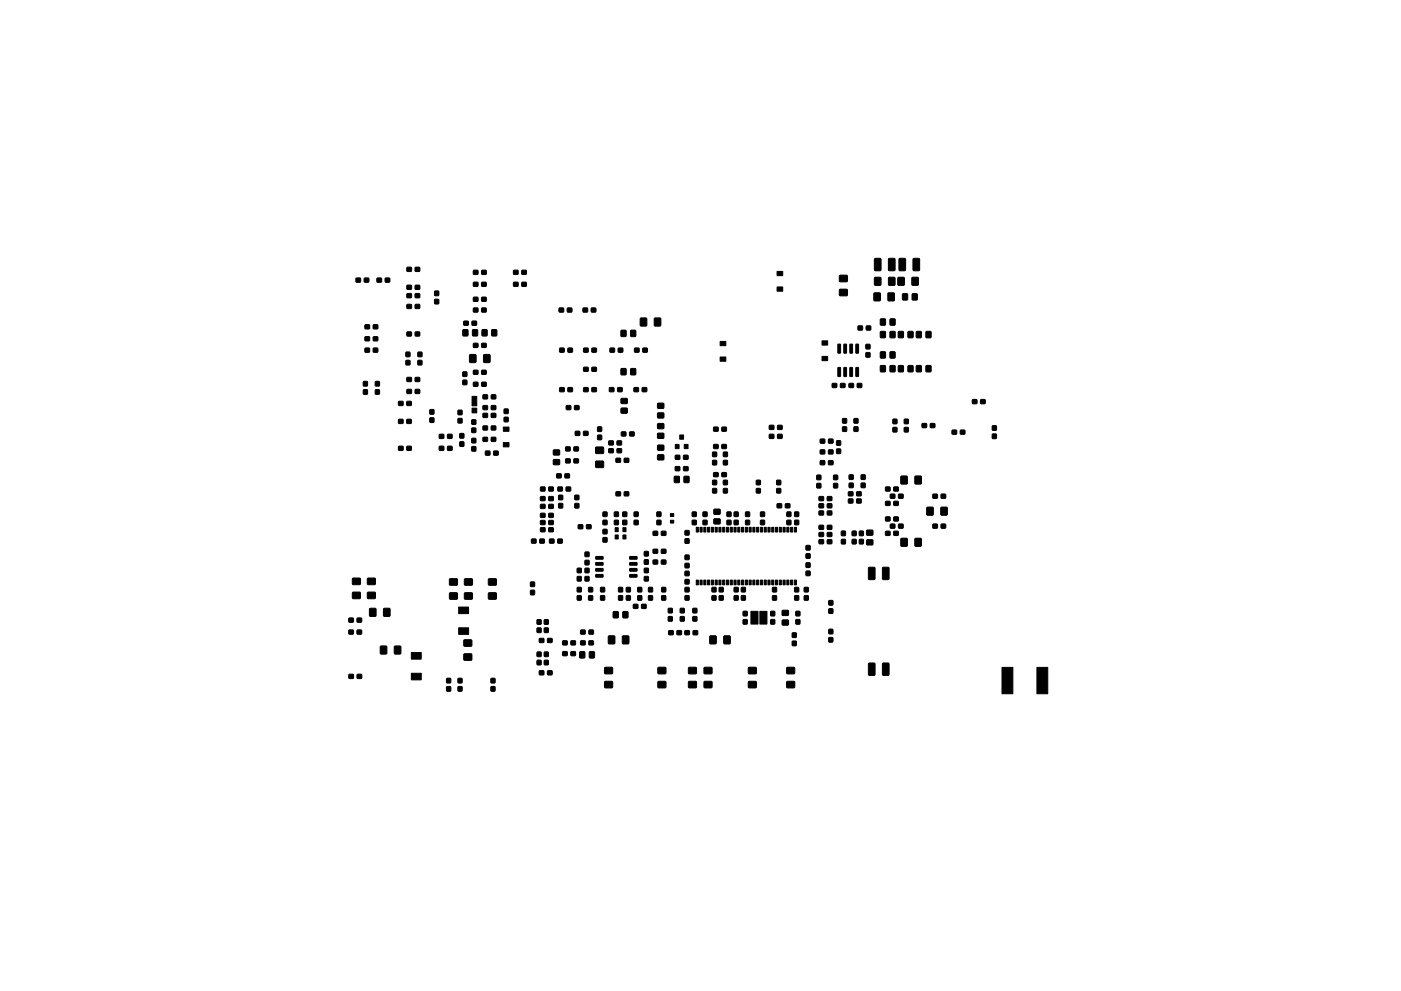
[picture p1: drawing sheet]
<svg xmlns="http://www.w3.org/2000/svg" width="297mm" height="210mm" viewBox="0 0 297 210" stroke-linecap="round" stroke-linejoin="round" font-family="sans-serif">
<g fill="#000" stroke="#000" stroke-width=".21">
<path d="M75.5 59h.9v.8l-.9 .1zM77.3 59h.8l.1 .8-.9 .1zM79.9 59h.9l.1 .8-.9 .1zM81.7 59h.9v.8l-.9 .1zM86.3 56.7h.9v.8l-.9 .1zM88 56.7h.9l.1 .8-.9 .1zM100.4 59.9h.9v.8h-.9zM100.4 57.4h.9v.8h-.9zM102.1 59.9h.9l.1 .8h-.9zM102.1 57.4h.9l.1 .8h-.9zM108.9 59.9h.9v.8h-.9zM108.9 57.4h.9v.8h-.9z"/>
<path d="M110.7 59.9h.8l.1 .8h-.9zM110.7 57.4h.8l.1 .8h-.9zM164.8 57.6h1.2v.9h-1.2zM178 58.4h1.6v1.3h-1.6zM185.5 58.9h1.2v1.6h-1.3zM185.5 54.9l1.1-.1 .2 .2v2.2l-.2 .2-1 .1-.2-.2zM188.4 58.9h1.3v1.6h-1.3zM188.4 54.9l1.2-.1 .2 .2v2.2l-.2 .2-1 .1-.2-.2zM190.4 58.9h1.3v1.6h-1.3zM190.7 54.9l1.1-.1 .2 .2v2.2l-.1 .2-1.1 .1-.2-.2zM193.4 58.9h1.3l-.1 1.6h-1.2zM193.6 54.9l1.2-.1 .2 .2v2.2l-.2 .2-1 .1-.2-.2z"/>
<path d="M77.4 68.9h.9v.8l-.9 .1zM77.4 71.5h.9v.8h-.9zM77.4 73.9h.9v.8h-.9zM79.2 68.9h.9v.8l-.9 .1zM79.2 71.5h.9v.8h-.9zM79.2 73.9h.9v.8h-.9zM86.1 76.5h.8v.9h-.8zM86.1 74.7l.8 .1v.9l-.8-.1zM86.3 60.5h.9v.8l-.9 .1zM86.3 70.5l.9-.1v.8l-.9 .1zM86.3 62.3h.9v.8l-.9 .1zM86.3 64.6h.9v.8h-.9z"/>
<path d="M88 60.5h.9l.1 .8-.9 .1zM88 70.5l.9-.1 .1 .8-.9 .1zM88 62.3h.9l.1 .8-.9 .1zM88 64.6h.9l.1 .8h-.9zM88.6 76.5h.8v.9h-.8zM88.6 74.7l.8 .1v.9l-.8-.1zM92.2 63.5l.8 .1v.9l-.8-.1zM92.2 61.8h.8v.9h-.8zM98.1 78.9h.9l-.1 1-.8-.1zM98.2 70h1v1.2h-1zM98.4 68.2h.8l.1 .8h-.9zM99.6 75.3h1.3v1.6h-1.3z"/>
<path d="M100.1 68.2h.9v.8h-.9zM100.2 70h1v1.2h-1zM100.4 65.4h.9v.8h-.9zM100.4 63.1h.9v.8h-.9zM100.4 72.9h.9v.8h-.9zM100.4 78.6h.9v.8h-.9zM102.1 65.4h.9l.1 .8h-.9zM102.1 63.1h.9l.1 .8h-.9zM102.1 72.9h.9l.1 .8h-.9zM102.1 78.6h.9l.1 .8h-.9zM102.2 70h1.1l-.1 1.2h-1zM102.6 75.3h1.3l-.1 1.6h-1.2z"/>
<path d="M104.3 70h1v1.2h-1zM118.6 65.4h.9v.8h-.9zM118.7 73.9h.9v.8h-.9zM120.3 65.4h.9v.8h-.9zM120.4 73.9h.9l.1 .8h-.9zM123.6 65.4h.9l.1 .8h-.9zM123.8 77.9h.9v.8l-.9 .1zM123.8 73.9h.9v.8h-.9zM125.4 65.4h.9v.8h-.9zM125.5 77.9h.9v.8l-.9 .1zM125.5 73.9h.9v.8h-.9zM129.4 73.9h.8l.1 .8h-.9z"/>
<path d="M131.1 73.9h.9v.8h-.9zM131.7 70.1h1v1.3l-1-.1zM131.7 78.2l1 .1v1.2h-1zM133.7 70.1h1.1l-.1 1.3-1-.1zM133.7 78.2l1.1 .1-.1 1.2h-1zM134.6 73.9h.9v.8h-.9zM135.8 67.5h1.3v1.6h-1.3zM136.3 73.9h.9v.8h-.9zM138.8 67.5h1.3l-.1 1.6h-1.2zM152.7 72.4h1.2v.9h-1.2zM152.7 75.7h1.2v.9h-1.2zM164.8 60.9h1.2v.9h-1.2z"/>
<path d="M174.3 72.3h1.2v.9h-1.2zM174.3 75.6h1.2v.9h-1.2zM177.7 78l.5 .1v1.7l-.1 .1-.5-.1zM177.7 73l.5 .1v1.7l-.1 .1-.5-.1zM178.9 78l.6 .1v1.7l-.1 .1-.5-.1zM178.9 73l.6 .1v1.7l-.1 .1-.5-.1zM178 61.4h1.6v1.3h-1.6zM180.2 78l.6 .1v1.7l-.2 .1-.4-.1zM180.2 73l.6 .1v1.7l-.2 .1-.4-.1zM181.5 78l.5 .1v1.7l-.1 .1-.5-.1zM181.5 73l.5 .1v1.7l-.1 .1-.5-.1zM181.9 69.2h.9l.1 .8h-1z"/>
<path d="M183.6 74.8l.8 .1v.9l-.8-.1zM183.6 73.1h.8v.9h-.8zM183.7 69.2h.9v.8h-.9zM185.3 62.2h1.3v1.6h-1.3zM186.7 77.6h1v1.3l-1-.1zM186.7 67.7h1v1.3l-1-.1zM186.7 74.7h1v1.2h-1zM186.7 70.4h1v1.2h-1zM188.3 62.2h1.3v1.6h-1.3zM188.7 77.6h1.1l-.1 1.3-1-.1zM188.7 67.7h1.1l-.1 1.3-1-.1zM188.7 74.7h1.1l-.1 1.2h-1z"/>
<path d="M188.7 70.4h1.1l-.1 1.2h-1zM190.5 70.4h1v1.2h-1zM190.5 77.6h1v1.3l-1-.1zM191.4 62.4h1v1.2h-1zM192.5 70.4h1.1l-.1 1.2h-1zM192.5 77.6h1.1l-.1 1.3-1-.1zM193.4 62.4h1.1l-.1 1.2h-1zM194.3 70.4h1v1.2h-1zM194.3 77.6h1v1.3l-1-.1zM196.4 70.4h1l-.1 1.2h-1zM196.4 77.6h1l-.1 1.3-1-.1zM77.1 82.7h.8v.9h-.9z"/>
<path d="M77.1 81h.8v.9h-.9zM79.6 82.7h.8v.9h-.8zM79.6 81h.8v.9h-.8zM84.5 89h.9v.8h-.9zM84.5 94.7h.9v.8h-.9zM84.5 85.2h.9v.8h-.9zM86.3 89h.9v.8h-.9zM86.3 94.7h.9v.8h-.9zM86.3 85.2h.9v.8h-.9zM86.3 80.1h.9v.8h-.9zM86.3 82.6h.9v.8l-.9 .1zM88 80.1h.9l.1 .8h-.9z"/>
<path d="M88 82.6h.9l.1 .8-.9 .1zM91.2 88.7h.8v.9h-.9zM91.2 86.9h.8v1l-.9-.1zM93.2 92.2h.9v.8h-.9zM93.2 94.7h.9v.8h-.9zM94.9 92.2h.9v.8h-.9zM94.9 94.7h.9v.8h-.9zM97.1 88.8h.9l-.1 .9h-.8zM97.1 87.1h.9l-.1 .9-.8-.1zM97.5 92h.8v.9h-.8zM97.5 93.8h.8v.9h-.8zM98.1 80.7h.9l-.1 .9h-.8z"/>
<path d="M100.1 84.1h1v2h-1zM100.1 86.6h1v1h-1zM100.1 90.8l.8 .1-.1 .9-.8-.1zM100.1 89.1h.8l-.1 .9h-.8zM100.1 94.8h.8l-.1 .9h-.8zM100.1 93h.8l-.1 1-.8-.1zM100.4 81.1h.9v.8h-.9zM102.1 81.1h.9l.1 .8h-.9zM102.4 86.1h.9l.1 .8h-1zM102.4 92.8h.9l.1 .8h-1zM102.4 87.7h.9l.1 .8-1 .1zM102.4 90.4h.9l.1 .8h-1z"/>
<path d="M102.4 83.8h.9l.1 .8h-1zM102.9 95.7h.9l.1 .8-.9 .1zM104.2 86.1h.9v.8h-.9zM104.2 92.8h.9v.8h-.9zM104.2 87.7h.9v.8l-.9 .1zM104.2 90.4h.9v.8h-.9zM104.2 83.8h.9v.8h-.9zM104.7 95.7h.9v.8l-.9 .1zM106.9 86.8h.8v.9h-.8zM106.9 88.6h.8v.9l-.8-.1zM106.7 90.6h1.2v.9h-1.2zM106.7 93.9h1.2v.9h-1.2z"/>
<path d="M117.4 97.5h1.2v1l-1.2 .1zM117.4 95.5h1.2v1h-1.2zM118.7 82.3h.9v.8h-.9zM120 97.4h.8l.1 .8h-.9zM120 94.8h.8l.1 .8-.9 .1zM120.1 86.1h.9v.8h-.9zM120.4 82.3h.9l.1 .8h-.9zM121.7 97.4h.9v.8h-.9zM121.7 94.8h.9v.8l-.9 .1zM121.8 86.1h.9l.1 .8h-1zM122 91.5h.9v.8l-.9 .1zM123.7 91.5h.9l.1 .8-.9 .1z"/>
<path d="M123.8 82.3h.9v.8h-.9zM125.5 82.3h.9v.8h-.9zM126.7 92.3l.8 .1v.9l-.8-.1zM126.7 90.6h.8v.9h-.8zM126.3 94.9h1.6v1.3h-1.6zM126.3 97.9h1.6v1.2l-1.6 .1zM129.1 93.6h.9v.8h-.9zM129.1 95.2h.9v.8h-.9zM129.2 82.3h.9l.1 .8h-1zM130.6 97.3l.9-.1v.8l-.9 .1zM130.8 93.6h.9l.1 .8h-.9zM130.8 95.2h.9l.1 .8h-.9z"/>
<path d="M131 82.3h.9v.8h-.9zM131.8 91.7l.9-.1v.9h-.9zM131.7 86.6h1.2l.1 1h-1.3zM131.7 84.6h1.2l.1 1h-1.3zM132.4 97.3l.9-.1v.8l-.9 .1zM133.5 91.7l.9-.1v.9h-.9zM134.4 82.3h.9l.1 .8h-1zM136.2 82.3h.9v.8h-.9zM139.5 87.6h1.2v1l-1.2 .1zM139.5 85.6h1.2v1h-1.2zM139.5 92l1.2-.1v1l-1.2 .1zM139.5 89.9h1.2v1h-1.2z"/>
<path d="M139.5 96.5h1.2v1h-1.2zM139.5 94.5h1.2v1h-1.2zM143.2 99h.9v.8l-.9 .1zM143.2 96.6h.9v.8h-.9zM143.2 94.3h.8v.9h-.8zM144.1 92.3h.8v.9h-.8zM144.9 99h.9l.1 .8-.9 .1zM144.9 96.6h.9l.1 .8h-.9zM145.1 94.3h.8v.9h-.8zM151.1 95.9l.8 .1v.9l-.8-.1zM151.1 97.7h.8v.9h-.8zM151.3 94.3h.9l.1 .8-1 .1z"/>
<path d="M151.3 90.6h.9l.1 .8-1 .1zM153.1 94.3h.9v.8l-.9 .1zM153.1 90.6h.9v.8l-.9 .1zM153.4 95.9l.8 .1v.9l-.8-.1zM153.4 97.7h.8v.9h-.8zM163.1 92.2h.9l.1 .8h-.9zM163.1 90.3h.9l.1 .8h-.9zM164.9 92.2h.9v.8h-.9zM164.9 90.3h.9v.8h-.9zM173.9 93.2h.9l.1 .8h-1zM173.9 97.8l.9-.1 .1 .9h-1zM173.9 95.5h.9l.1 .8h-1z"/>
<path d="M175.7 93.2h.9v.8h-.9zM175.7 97.8l.9-.1v.9h-.9zM175.7 95.5h.9v.8h-.9zM176.5 81.4h.9v.8h-.9zM177.4 93.5l.8 .1v.9l-.8-.1zM177.4 95.3h.8v.9h-.8zM178.2 81.4h.9v.8h-.9zM178.7 90.6h.8v.9h-.9zM178.7 88.8l.8 .1v.9l-.9-.1zM180 81.4h.9l.1 .8h-1zM181.1 90.6h.8v.9h-.8zM181.1 88.8l.8 .1v.9l-.8-.1z"/>
<path d="M181.8 81.4h.9v.8h-.9zM189.3 90.7h.9l-.1 .9h-.8zM189.3 89h.9l-.1 .9h-.8zM191.7 90.7h.9l-.1 .9h-.8zM191.7 89h.9l-.1 .9h-.8zM195.5 89.9h.9v.8h-.9zM197.3 89.9h.9v.8h-.9zM201.9 91.3h.9v.8h-.9zM203.6 91.3h.9l.1 .8h-.9zM206.2 84.8h.9v.8h-.9zM207.9 84.8h.9l.1 .8h-.9zM210.4 92.1h.8v.9h-.8z"/>
<path d="M210.4 90.4h.8v.9h-.8zM112.7 114.4h.9v.8h-.9zM114.5 114.4h.9v.8h-.9zM114.6 103.3h.9v.8l-.9 .1zM114.6 105.4h.9v.8h-.9zM114.6 112h.9v.8h-.9zM114.6 110.5l.9-.1v.9h-.9zM114.6 108.9h.9v.8l-.9 .1zM114.6 107h.9v.8l-.9 .1zM116.4 103.3h.9v.8l-.9 .1zM116.4 105.4h.9v.8h-.9zM116.4 112h.9v.8h-.9z"/>
<path d="M116.4 110.5l.9-.1v.9h-.9zM116.4 108.9h.9v.8l-.9 .1zM116.4 107h.9v.8l-.9 .1zM116.5 114.4h.9l.1 .8h-1zM118 100.6l.9-.1 .1 .8-.9 .1zM118.3 114.4h.9v.8h-.9zM118.3 103.3h.9v.8l-.9 .1zM118.5 106.8l.8 .1v.9l-.8-.1zM118.5 105.1h.8v.9h-.8zM119.8 100.6l.9-.1v.8l-.9 .1zM120.1 103.3h.8l.1 .8-.9 .1zM121.9 106.8l.8 .1v.9l-.8-.1z"/>
<path d="M121.9 105.1h.8v.9h-.8zM122.6 111.3h.9v.8l-.9 .1zM124.1 117.2h.8l-.1 .9-.8-.1zM124.1 118.9h.8l-.1 .9h-.8zM124.4 111.3h.9v.8l-.9 .1zM126.3 118.1h1.5l.1 .5-1.5 .1zM126.3 119.4l1.5-.1 .1 .5-1.5 .1zM127.9 112.3h.8v1l-.9-.1zM127.9 114.1h.8v.9h-.9zM127.9 110.4h.8v.9h-.9zM127.9 108.6l.8 .1v.9l-.9-.1zM130.3 110.4h.8v.9h-.8z"/>
<path d="M130.3 108.6l.8 .1v.9l-.8-.1zM130.4 112h.7v.8h-.7zM130.4 113.5h.7v.9h-.7zM130.6 104.4l.9-.1v.9h-.9zM132.1 108.6l.8 .1-.1 .9-.8-.1zM132.1 110.4h.8l-.1 .9h-.8zM132.1 112h.6v.8h-.6zM132.1 113.5h.6v.9h-.6zM132.4 104.4l.9-.1v.9h-.9zM133.5 119.4l1.5-.1 .1 .5-1.5 .1zM133.5 118.1h1.5l.1 .5-1.5 .1zM134.5 110.4h.8v.9h-.8z"/>
<path d="M134.5 108.6l.8 .1v.9l-.8-.1zM136.6 117h.9l-.1 1-.8-.1zM136.6 118.8h.9l-.1 .9h-.8zM138.5 112.7h.9v.8l-.9 .1zM138.5 118.8h.9v.8l-.9 .1zM138.5 116.6l.9-.1v.8l-.9 .1zM139.3 110.4h.8v.9h-.8zM139.3 108.6l.8 .1v.9l-.8-.1zM140.2 112.7h.9l.1 .8-.9 .1zM140.2 118.8h.9l.1 .8-.9 .1zM140.2 116.6l.9-.1 .1 .8-.9 .1zM142.1 109h.7v.6h-.7z"/>
<path d="M142.1 110.4h.7v.6h-.7zM143 101.1h1v1.3l-1-.1zM145 101.1h1.1l-.1 1.3-1-.1zM145.3 112.6h.8v.9h-.9zM145.3 114.3l.8 .1v.9l-.9-.1zM145.3 117.8h.8v.9h-.9zM145.3 119.5l.8 .1v.9l-.9-.1zM146.8 108.6l.8 .1v.9l-.8-.1zM146.8 110.4h.8v.9h-.8zM147.6 111.9h.5v1h-.5zM148.4 111.9h.5v1h-.5zM149.2 111.9h.5v1h-.5z"/>
<path d="M149.1 110.4h.8v.9h-.8zM149.1 108.6l.8 .1v.9l-.8-.1zM150 111.9h.5v1h-.5zM150.8 111.9h.5v1h-.5zM151.6 111.9h.5v1h-.5zM151.1 101.9h.8v.9h-.8zM151.1 103.7h.8v.9h-.8zM151.3 100.3h.9l.1 .8h-1zM152.4 111.9h.5v1h-.5zM151.4 110.1h1.2l.1 1h-1.3zM151.4 108.1h1.2l.1 1h-1.3zM153.2 111.9h.5v1h-.5z"/>
<path d="M153.1 100.3h.9v.8h-.9zM154 111.9h.5v1h-.5zM153.4 101.9h.8v.9h-.8zM153.4 103.7h.8v.9h-.8zM154.8 111.9h.5v1h-.5zM154.2 108.6l.8 .1-.1 .9-.8-.1zM154.2 110.4h.8l-.1 .9h-.8zM155.6 111.9h.5v1h-.5zM155.7 110.4h.8v.9h-.8zM155.7 108.6l.8 .1v.9l-.8-.1zM156.4 111.9h.5v1h-.5zM157.2 111.9h.5v1h-.5z"/>
<path d="M158 111.9h.5v1h-.5zM158.1 108.6l.8 .1v.9l-.8-.1zM158.1 110.4h.8v.9h-.8zM158.8 111.9h.5v1h-.5zM159.6 111.9h.5v1h-.5zM160.4 111.9h.5v1h-.5zM160.4 103.7h.8v.9h-.8zM160.4 101.9h.8v.9h-.8zM161.2 111.9h.5v1h-.5zM161.3 110.4h.8v.9h-.9zM161.3 108.6l.8 .1v.9l-.9-.1zM162 111.9h.5v1h-.5z"/>
<path d="M162.8 111.9h.5v1h-.5zM163.6 111.9h.5v1h-.5zM164.4 111.9h.5v1h-.5zM165.2 111.9h.5v1h-.5zM164.7 103.7h.8v.9h-.8zM164.7 101.9h.8v.9h-.8zM164.8 106.9h.9v.8h-.9zM166 111.9h.5v1h-.5zM166.8 111.9h.5v1h-.5zM166.5 106.9h.9l.1 .8h-.9zM166.9 110.4h.8l-.1 .9h-.8zM166.9 108.6l.8 .1-.1 .9-.8-.1z"/>
<path d="M167.6 111.9h.5v1h-.5zM168.4 111.9h.5v1h-.5zM168.5 108.6l.8 .1v.9l-.8-.1zM168.5 110.4h.8v.9h-.8zM170.9 117.5h.8v.9h-.8zM170.9 115.8h.8v.9h-.8zM170.9 119.4l.8 .1v.9l-.8-.1zM173.2 100.8l.8 .1v.9l-.8-.1zM173.2 102.6h.8v.9h-.8zM173.7 111.5h.9v.8h-.9zM173.7 106.9h.9v.8h-.9zM173.7 108.4h.9v.8l-.9 .1z"/>
<path d="M173.7 113h.9v.8h-.9zM173.7 105.4h.9v.8h-.9zM173.7 114.5h.9v.8l-.9 .1zM175.4 111.5h.9l.1 .8h-1zM175.4 106.9h.9l.1 .8h-1zM175.4 108.4h.9l.1 .8-1 .1zM175.4 113h.9l.1 .8h-1zM175.4 105.4h.9l.1 .8h-1zM175.4 114.5h.9l.1 .8-1 .1zM176.8 100.8l.8 .1v.9l-.9-.1zM176.8 102.6h.8v.9h-.9zM178.4 112.7h.8v.9h-.8z"/>
<path d="M178.4 114.5h.8v.9h-.8zM179.9 105.9h.9v.8h-.9zM179.9 104.4l.9-.1v.9h-.9zM180.1 102.5h.8v.9h-.9zM180.1 100.8h.8v.9h-.9zM180.7 114.5h.8v.9h-.8zM180.7 112.7h.8v.9h-.8zM181.6 105.9h.9l.1 .8h-.9zM181.6 104.4l.9-.1 .1 .9h-.9zM182.2 114.5h.8v.9h-.8zM182.2 112.7h.8v.9h-.8zM182.6 102.5h.8v.9h-.8z"/>
<path d="M182.6 100.8h.8v.9h-.8zM183.8 114.6l1.2-.1v1l-1.2 .1zM183.8 112.5h1.2v1h-1.2zM187.8 112.7h.9v.8l-.9 .1zM187.8 109.7h.9v.8h-.9zM187.8 106.4h.9v.8h-.9zM187.8 103.3h.9v.8l-.9 .1zM188.8 111.2h.9v.8h-.9zM188.8 104.9h.9v.8h-.9zM189.5 112.7h.9v.8l-.9 .1zM189.5 109.7h.9v.8h-.9zM189.5 106.4h.9v.8h-.9z"/>
<path d="M189.5 103.3h.9v.8l-.9 .1zM190.5 111.2h.9l.1 .8h-.9zM190.5 104.9h.9l.1 .8h-.9zM191 114.3h1.3v1.6l-1.3-.1zM191 101l1.3 .1v1.6l-1.3-.1zM194 114.3h1.3v1.6l-1.3-.1zM194 101l1.3 .1v1.6l-1.3-.1zM196.5 107.7h1.3v1.6l-1.3-.1zM197.8 104.9h.9v.8h-.9zM197.8 111.2h.9v.8h-.9zM199.6 104.9h.8l.1 .8h-.9zM199.6 111.2h.8l.1 .8h-.9z"/>
<path d="M199.5 107.7h1.3v1.6l-1.3-.1zM74 131.2l.9-.1v.9h-.9zM74 133.7h.9v.8h-.9zM74.8 125.7h1.5l.1 1.2-1.6 .1zM74.8 122.7h1.5l.1 1.3h-1.6zM75.7 131.2l.9-.1 .1 .9h-1zM75.7 133.7h.9l.1 .8h-1zM77.9 125.7h1.6l.1 1.2-1.6 .1zM77.9 122.7h1.6l.1 1.3h-1.6zM78.4 129.1h1.3v1.6h-1.3zM80.7 137.1h1.3l-.1 1.6h-1.2zM81.4 129.1h1.3l-.1 1.6h-1.3z"/>
<path d="M83.7 137.1h1.2v1.6h-1.3zM87.2 138.4h2.1v1.4h-2.1zM95.3 122.8h1.6l.1 1.3h-1.6zM95.3 125.8h1.6l.1 1.3h-1.6zM97.2 133.2h2.1v1.4h-2.1zM97.2 128.8h2.1v1.4h-2.1zM98.4 138.8l1.6-.1v1.3l-1.6 .1zM98.4 135.8h1.6v1.2l-1.6 .1zM98.5 122.8h1.6v1.3h-1.6zM98.5 125.8h1.6v1.3h-1.6zM103.6 122.8h1.6v1.3h-1.6zM103.6 125.8h1.6v1.3h-1.6z"/>
<path d="M112.5 125.3h.8v.9l-.8-.1zM112.5 123.5h.8v.9h-.8zM113.9 138.4h.8v.9h-.8zM113.9 131.5h.8v.9h-.8zM113.9 133.3h.8v.9l-.8-.1zM114.4 135.5h.9v.8h-.9zM115.4 131.5h.8v.9h-.8zM115.4 133.3h.8v.9l-.8-.1zM115.4 138.4h.8v.9h-.8zM116.1 135.5h.9v.8h-.9zM119.3 138.3h.9v.8h-.9zM119.3 136h.9v.8h-.9z"/>
<path d="M121.1 138.3h.9v.8h-.9zM121.1 136h.9v.8h-.9zM122.4 122.3l.8 .1v.9l-.8-.1zM122.4 120.6h.8v.9h-.8zM122.4 126.4h.8v.9h-.8zM122.4 124.6l.8 .1v.9l-.8-.1zM122.9 138.3h1.1l-.1 1.3-1-.1zM123.1 136h.9l.1 .8h-1zM123.1 133.7h.9l.1 .8h-1zM124.1 122.3l.8 .1-.1 .9-.8-.1zM124.1 120.6h.8l-.1 .9h-.8zM124.8 124.6l.8 .1v.9l-.8-.1z"/>
<path d="M124.8 126.4h.8v.9h-.8zM124.9 136h.9v.8h-.9zM124.9 133.7h.9v.8h-.9zM125 138.3h1v1.3l-1-.1zM126.3 120.6h1.5l.1 .5-1.5 .1zM126.3 121.9h1.5l.1 .5-1.5 .1zM127.4 124.6l.8 .1v.9l-.9-.1zM127.4 126.4h.8v.9h-.9zM129 135h1.3v1.6l-1.3-.1zM130 129.8h1.1l-.1 1.3-1-.1zM131.2 124.6l.8 .1v.9l-.8-.1zM131.2 126.4h.8v.9h-.8z"/>
<path d="M132.1 129.8h1v1.3l-1-.1zM132 135h1.3v1.6l-1.3-.1zM132.8 124.6l.8 .1v.9l-.8-.1zM132.8 126.4h.8v.9h-.8zM133.5 121.9h1.5l.1 .5-1.5 .1zM133.5 120.6h1.5l.1 .5-1.5 .1zM134.3 128.2h.9v.8l-.9 .1zM135.2 126.4h.9l-.1 .9h-.8zM135.2 124.6l.9 .1-.1 .9-.8-.1zM136.1 128.2h.8l.1 .8-.9 .1zM136.6 122.3l.9 .1-.1 .9-.8-.1zM136.6 120.6h.9l-.1 .9h-.8z"/>
<path d="M137.5 124.6l.8 .1v.9l-.8-.1zM137.5 126.4h.8v.9h-.8zM140.3 124.6l.8 .1v.9l-.8-.1zM140.3 126.4h.8v.9h-.8zM141.7 129.1h.8v.9h-.8zM141.7 130.8l.8 .1v.9l-.8-.1zM141.8 133.8h.9v.8l-.9 .1zM143.5 133.8h.9l.1 .8-.9 .1zM144.2 129.1h.9l-.1 .9h-.8zM144.2 130.8l.9 .1-.1 .9-.8-.1zM145.3 123h.8v.9h-.9zM145.3 121.2h.8v.9h-.9z"/>
<path d="M145.3 124.6l.8 .1v.9l-.9-.1zM145.3 126.4h.8v.9h-.9zM145.2 133.8h.9l.1 .8-1 .1zM146.9 129.1h.8v.9h-.8zM146.9 130.8l.8 .1v.9l-.8-.1zM147.6 123.1h.5v1h-.5zM147 133.8h.9v.8l-.9 .1zM148.4 123.1h.5v1h-.5zM149.2 123.1h.5v1h-.5zM150 123.1h.5v1h-.5zM150.8 123.1h.5v1h-.5zM151.6 123.1h.5v1h-.5z"/>
<path d="M151 126.4h.8v.9h-.8zM151 124.6l.8 .1v.9l-.8-.1zM150.5 135h1.3v1.6l-1.3-.1zM152.4 123.1h.5v1h-.5zM152.5 124.6l.8 .1v.9l-.8-.1zM152.5 126.4h.8v.9h-.8zM153.2 123.1h.5v1h-.5zM154 123.1h.5v1h-.5zM153.5 135h1.3v1.6l-1.3-.1zM154.8 123.1h.5v1h-.5zM155.6 123.1h.5v1h-.5zM155.7 126.4h.8v.9h-.8z"/>
<path d="M155.7 124.6l.8 .1v.9l-.8-.1zM156.4 123.1h.5v1h-.5zM157.2 123.1h.5v1h-.5zM157.2 124.6l.8 .1v.9l-.8-.1zM157.2 126.4h.8v.9h-.8zM158 123.1h.5v1h-.5zM157.6 129.7h.8v1l-.8-.1zM157.6 131.5h.8v.9h-.8zM158.8 123.1h.5v1h-.5zM159.2 129.7h1.5v2.7h-1.5zM159.6 123.1h.5v1h-.5zM160.4 123.1h.5v1h-.5z"/>
<path d="M161.1 129.7h1.5v2.7h-1.5zM161.2 123.1h.5v1h-.5zM162 123.1h.5v1h-.5zM162.8 123.1h.5v1h-.5zM163.6 123.1h.5v1h-.5zM163.4 129.7h.9l-.1 1-.8-.1zM163.4 131.5h.9l-.1 .9h-.8zM164.4 123.1h.5v1h-.5zM163.8 124.6l.8 .1v.9l-.8-.1zM163.8 126.4h.8v.9h-.8zM165.2 123.1h.5v1h-.5zM166 123.1h.5v1h-.5z"/>
<path d="M166.8 123.1h.5v1h-.5zM165.9 131.6h1.2v1h-1.2zM165.9 129.5h1.2v1l-1.2 .1zM167.6 123.1h.5v1h-.5zM168.4 123.1h.5v1h-.5zM168 136l.8 .1v.9l-.8-.1zM168 134.3h.8v.9h-.8zM168.5 126.4h.8v.9h-.8zM168.5 124.6l.8 .1v.9l-.8-.1zM168.8 131.5h.8v.9h-.9zM168.8 129.7h.8v1l-.9-.1zM170.5 126.4h.9l-.1 .9h-.8z"/>
<path d="M170.5 124.6l.9 .1-.1 .9-.8-.1zM170.9 121.2h.8v.9h-.8zM175.7 135.3h.9l-.1 .9h-.8zM175.7 133.5l.9 .1-.1 .9-.8-.1zM175.7 129.2h.9l-.1 .9h-.8zM175.7 127.4l.9 .1-.1 .9-.8-.1zM184.2 120.4l1.1-.1 .2 .2v2.3l-.1 .2h-1.1l-.2-.2zM187.2 120.4l1.1-.1 .2 .2v2.2l-.1 .3h-1.1l-.2-.1zM74 143.1h.9v.8h-.9zM75.7 143.1h.9l.1 .8h-.9zM87.2 142.8h2.1v1.4h-2.1zM94.7 145.7h.8v.9h-.8z"/>
<path d="M94.7 144h.8v.9l-.8-.1zM97.1 144h.9l-.1 .9-.8-.1zM97.1 145.7h.9l-.1 .9h-.8zM104.1 145.7h.8v.9h-.8zM104.1 144h.8v.9l-.8-.1zM113.9 140.1h.8v.9h-.8zM114.4 142.3h.9v.8l-.9 .1zM115.4 140.1h.8v.9h-.8zM116.1 142.3h.9v.8l-.9 .1zM128.2 144.6h1.6l.1 1.3h-1.7zM128.2 141.6h1.6l.1 1.3h-1.7zM139.5 144.6h1.6l.1 1.3h-1.6z"/>
<path d="M139.5 141.6h1.6l.1 1.3h-1.6zM146 141.6h1.6v1.3h-1.6zM146 144.6h1.6v1.3h-1.6zM149.3 144.6h1.6v1.3h-1.6zM149.3 141.6h1.6v1.3h-1.6zM158.7 144.6h1.6v1.3h-1.6zM158.7 141.6h1.6v1.3h-1.6zM166.8 141.6h1.6l.1 1.3h-1.6zM166.8 144.6h1.6l.1 1.3h-1.6zM184.2 140.7h1.1l.2 .1v2.3l-.1 .2h-1.1l-.2-.1zM187.2 140.7h1.1l.2 .1v2.3l-.1 .2h-1.1l-.2-.1zM212.4 141.6h2.3v5.6h-2.3z"/>
<path d="M219.8 141.6h2.3v5.6h-2.3z"/>
</g>
</svg>
